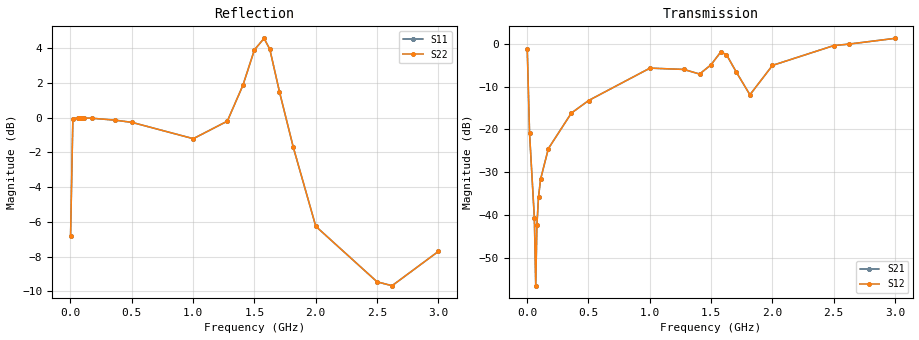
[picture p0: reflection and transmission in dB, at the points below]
!s-Parameter Generated by FASTRON Sdn. Bhd.
!FASTRON P/N : MICC-8R2X
!Keysight Technologies,E4991B,MY54100416,A.01.15
!Date: Fri Aug 28 10:59:28 2026
!Version  : Rev00 Fri Aug 28 10:59:28 2026
!Data & Calibration Information:
!PortZ  Port1:50+j0  Port2:50+j0
!When reading, reference impedance value at option line is always used.
! Remarks : This data is being provided solely for informational purposes.
!Freq	S11	S21	S12	S22
# Hz S dB R 50
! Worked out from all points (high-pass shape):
!   1601 points, 1 MHz to 3 GHz, reference 50 ohm
!   highest |S21| = 1.24 dB at 3 GHz (marker M1); lowest = -56.5 dB at 70.35 MHz (marker M2)
!   |S21| within 3 dB of the highest: start of sweep to 1.29 MHz; 2.289 GHz to end of sweep
!   lowest |S11| = -9.7 dB at 2.623 GHz (marker M3), VSWR 1.98, Z = 45.6 - j32.9 ohm
!   |S11| at or under -10 dB: nowhere
!   |S22| runs from -9.7 to 4.6 dB; largest |S21 - S12| = 0
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1000000  -6.79 61.3  -1.14 -27.2  -1.14 -27.2  -6.79 61.3
1.974375e7  -0.05 5.2  -20.89 -83.7  -20.89 -83.7  -0.05 5.2
5.910562e7  -0.01 0.5  -40.73 -81.2  -40.73 -81.2  -0.01 0.5
7.035188e7  -0.01 -0.0  -56.46 21.2  -56.46 21.2  -0.01 -0.0
7.972375e7  -0.01 -0.4  -42.37 78.5  -42.37 78.5  -0.01 -0.4
9.284438e7  -0.01 -0.9  -35.78 84.2  -35.78 84.2  -0.01 -0.9
1.097138e8  -0.02 -1.5  -31.61 85.4  -31.61 85.4  -0.02 -1.5
1.734425e8  -0.03 -3.4  -24.47 85.0  -24.47 85.0  -0.03 -3.4
3.6088e8  -0.14 -8.9  -16.19 79.7  -16.19 79.7  -0.14 -8.9
5.014581e8  -0.27 -12.5  -13.26 75.6  -13.26 75.6  -0.27 -12.5
1.001916e9  -1.21 -31.2  -5.70 60.4  -5.70 60.4  -1.21 -31.2
1.279324e9  -0.20 -29.3  -6.01 72.8  -6.01 72.8  -0.20 -29.3
1.406781e9  1.87 -19.2  -7.09 112.9  -7.09 112.9  1.87 -19.2
1.5005e9  3.91 0.1  -4.91 -179.6  -4.91 -179.6  3.91 0.1
1.579224e9  4.57 17.8  -1.93 -139.8  -1.93 -139.8  4.57 17.8
1.626083e9  3.94 21.8  -2.57 -128.3  -2.57 -128.3  3.94 21.8
1.704807e9  1.49 22.8  -6.56 -101.5  -6.56 -101.5  1.49 22.8
1.817269e9  -1.70 11.4  -11.92 -40.1  -11.92 -40.1  -1.70 11.4
2.000958e9  -6.26 -18.0  -5.07 15.6  -5.07 15.6  -6.26 -18.0
2.501416e9  -9.46 -71.8  -0.44 19.7  -0.44 19.7  -9.46 -71.8
2.623251e9  -9.68 -78.6  -0.10 19.0  -0.10 19.0  -9.68 -78.6
3e9  -7.71 -101.2  1.24 20.5  1.24 20.5  -7.71 -101.2
